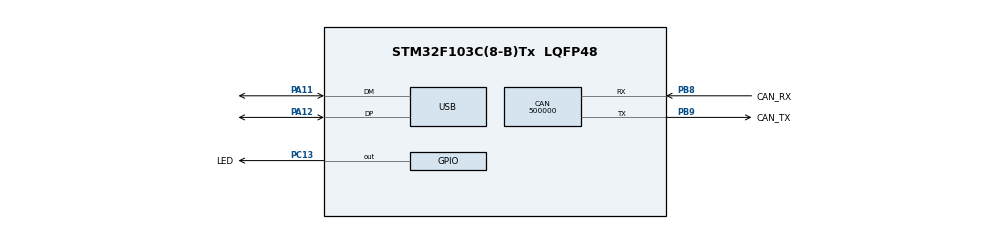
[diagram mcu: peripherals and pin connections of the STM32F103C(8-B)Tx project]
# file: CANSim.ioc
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CAN.CalculateBaudRate=500000
CAN.CalculateTimeBit=2000
CAN.CalculateTimeQuantum=666.6666666666666
Mcu.Family=STM32F1
Mcu.Name=STM32F103C(8-B)Tx
Mcu.Package=LQFP48
NVIC.PriorityGroup=NVIC_PRIORITYGROUP_4
NVIC.USB_LP_CAN1_RX0_IRQn=true\:0\:0\:false\:false\:true\:true\:false\:true
PA11.Mode=Device
PA11.Signal=USB_DM
PA12.Mode=Device
PA12.Signal=USB_DP
PA13.Mode=Serial_Wire
PA13.Signal=SYS_JTMS-SWDIO
PA14.Mode=Serial_Wire
PA14.Signal=SYS_JTCK-SWCLK
PB8.GPIO_Label=CAN_RX
PB8.Mode=CAN_Activate
PB8.Signal=CAN_RX
PB9.GPIO_Label=CAN_TX
PB9.Mode=CAN_Activate
PB9.Signal=CAN_TX
PC13-TAMPER-RTC.GPIO_Label=LED
PC13-TAMPER-RTC.PinState=GPIO_PIN_SET
PC13-TAMPER-RTC.Signal=GPIO_Output
PD0-OSC_IN.Mode=HSE-External-Oscillator
PD0-OSC_IN.Signal=RCC_OSC_IN
PD1-OSC_OUT.Mode=HSE-External-Oscillator
PD1-OSC_OUT.Signal=RCC_OSC_OUT
ProjectManager.HeapSize=0x200
ProjectManager.StackSize=0x400
ProjectManager.TargetToolchain=STM32CubeIDE
RCC.AHBFreq_Value=48000000
RCC.APB1CLKDivider=RCC_HCLK_DIV2
RCC.APB1Freq_Value=24000000
RCC.APB1TimFreq_Value=48000000
RCC.APB2Freq_Value=48000000
RCC.APB2TimFreq_Value=48000000
RCC.CortexFreq_Value=72000000
RCC.FlatMode=1
RCC.HCLKFreq_Value=48000000
RCC.HCLK_Value=72000000
RCC.HSEBYP_enable=false
RCC.HSE_Value=8000000
RCC.HSI_VALUE=8000000
RCC.PLLMUL=RCC_PLL_MUL6
RCC.PLLMult=RCC_PLL_MUL9
RCC.PLLSourceVirtual=RCC_PLLSOURCE_HSE
RCC.PLLXTPRE=RCC_PLLXTPRE_DIV1
RCC.PREDIV1CLKSource=RCC_PREDIV1_SOURCE_HSE
RCC.PREDIV1Factor=RCC_PREDIV1_DIV1
RCC.SYSCLKFreq_VALUE=48000000
RCC.SYSCLKSource=RCC_SYSCLKSOURCE_PLLCLK
RCC.SYSCLK_Value=72000000
RCC.USBFreq_Value=48000000
RCC.USB_Value=48000000
RCC.VCOOutput_Value=72000000
USB_DEVICE.CLASS_NAME_FS=CDC
USB_DEVICE.VirtualMode=Cdc
USB_DEVICE.VirtualModeFS=Cdc_FS
VP_USB_DEVICE_VS_USB_DEVICE_CDC_FS.Mode=CDC_FS
board=custom

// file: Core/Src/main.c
/* USER CODE BEGIN Header */
/**
 * CANSim – CAN Bus Simulator for STM32F103C8T6 (Blue Pill)
 *
 * USB CDC virtual COM port provides a CLI to control CAN traffic.
 * CAN TX/RX uses PB8/PB9 (AFIO remap 2) to avoid conflict with USB PA11/PA12.
 * CAN RX routes to FIFO1 so CAN1_RX1_IRQn is used (USB LP uses FIFO0 IRQ).
 */
/* USER CODE END Header */
#include "main.h"
#include "usb_device.h"

/* USER CODE BEGIN Includes */
#include "can_handler.h"
#include "cli.h"
#include "usb_cdc_handler.h"
/* USER CODE END Includes */

CAN_HandleTypeDef hcan;

void SystemClock_Config(void);
static void MX_GPIO_Init(void);
static void MX_CAN_Init(void);

int main(void)
{

  /* MCU Configuration--------------------------------------------------------*/

  /* Reset of all peripherals, Initializes the Flash interface and the Systick. */
  HAL_Init();

  /* Configure the system clock */
  SystemClock_Config();

  /* Initialize all configured peripherals */
  MX_GPIO_Init();
  MX_CAN_Init();
  MX_USB_DEVICE_Init();
  /* USER CODE BEGIN 2 */
  CDC_Handler_Init();
  CAN_Handler_Init();
  CLI_Init();
  /* USER CODE END 2 */

  /* Infinite loop */
  while (1)
  {

    /* USER CODE BEGIN 3 */
    CLI_Process();
    CAN_Handler_Process();
  }
  /* USER CODE END 3 */
}

void SystemClock_Config(void)
{
  RCC_OscInitTypeDef RCC_OscInitStruct = {0};
  RCC_ClkInitTypeDef RCC_ClkInitStruct = {0};
  RCC_PeriphCLKInitTypeDef PeriphClkInit = {0};

  /** Initializes the RCC Oscillators according to the specified parameters
  * in the RCC_OscInitTypeDef structure.
  */
  RCC_OscInitStruct.OscillatorType = RCC_OSCILLATORTYPE_HSE;
  RCC_OscInitStruct.HSEState = RCC_HSE_ON;
  RCC_OscInitStruct.HSEPredivValue = RCC_HSE_PREDIV_DIV1;
  RCC_OscInitStruct.HSIState = RCC_HSI_ON;
  RCC_OscInitStruct.PLL.PLLState = RCC_PLL_ON;
  RCC_OscInitStruct.PLL.PLLSource = RCC_PLLSOURCE_HSE;
  RCC_OscInitStruct.PLL.PLLMUL = RCC_PLL_MUL9;
  if (HAL_RCC_OscConfig(&RCC_OscInitStruct) != HAL_OK)
  {
    Error_Handler();
  }

  /** Initializes the CPU, AHB and APB buses clocks
  */
  RCC_ClkInitStruct.ClockType = RCC_CLOCKTYPE_HCLK|RCC_CLOCKTYPE_SYSCLK
                              |RCC_CLOCKTYPE_PCLK1|RCC_CLOCKTYPE_PCLK2;
  RCC_ClkInitStruct.SYSCLKSource = RCC_SYSCLKSOURCE_PLLCLK;
  RCC_ClkInitStruct.AHBCLKDivider = RCC_SYSCLK_DIV1;
  RCC_ClkInitStruct.APB1CLKDivider = RCC_HCLK_DIV2;
  RCC_ClkInitStruct.APB2CLKDivider = RCC_HCLK_DIV1;

  if (HAL_RCC_ClockConfig(&RCC_ClkInitStruct, FLASH_LATENCY_2) != HAL_OK)
  {
    Error_Handler();
  }
  PeriphClkInit.PeriphClockSelection = RCC_PERIPHCLK_USB;
  PeriphClkInit.UsbClockSelection = RCC_USBCLKSOURCE_PLL_DIV1_5;
  if (HAL_RCCEx_PeriphCLKConfig(&PeriphClkInit) != HAL_OK)
  {
    Error_Handler();
  }
}

static void MX_CAN_Init(void)
{

  hcan.Instance = CAN1;
  /* APB1=36 MHz, Prescaler=9 → TQ=250 ns
   * Bit = SYNC(1)+BS1(5)+BS2(2) = 8 TQ = 2 µs → 500 kbps, SP=75% */
  hcan.Init.Prescaler = 9;
  hcan.Init.Mode = CAN_MODE_NORMAL;
  hcan.Init.SyncJumpWidth = CAN_SJW_1TQ;
  hcan.Init.TimeSeg1 = CAN_BS1_5TQ;
  hcan.Init.TimeSeg2 = CAN_BS2_2TQ;
  hcan.Init.TimeTriggeredMode = DISABLE;
  hcan.Init.AutoBusOff = DISABLE;
  hcan.Init.AutoWakeUp = DISABLE;
  hcan.Init.AutoRetransmission = ENABLE;
  hcan.Init.ReceiveFifoLocked = DISABLE;
  hcan.Init.TransmitFifoPriority = DISABLE;
  if (HAL_CAN_Init(&hcan) != HAL_OK)
  {
    Error_Handler();
  }

}

static void MX_GPIO_Init(void)
{
  GPIO_InitTypeDef GPIO_InitStruct = {0};

  /* GPIO Ports Clock Enable */
  __HAL_RCC_GPIOC_CLK_ENABLE();
  __HAL_RCC_GPIOD_CLK_ENABLE();
  __HAL_RCC_GPIOA_CLK_ENABLE();
  __HAL_RCC_GPIOB_CLK_ENABLE();

  /*Configure GPIO pin Output Level */
  HAL_GPIO_WritePin(LED_GPIO_Port, LED_Pin, GPIO_PIN_SET);

  /*Configure GPIO pin : LED_Pin */
  GPIO_InitStruct.Pin = LED_Pin;
  GPIO_InitStruct.Mode = GPIO_MODE_OUTPUT_PP;
  GPIO_InitStruct.Pull = GPIO_NOPULL;
  GPIO_InitStruct.Speed = GPIO_SPEED_FREQ_LOW;
  HAL_GPIO_Init(LED_GPIO_Port, &GPIO_InitStruct);

}

void Error_Handler(void)
{
  __disable_irq();
  while (1)
  {
  }
}
